VERSION 5.7 ;
  NOWIREEXTENSIONATPIN ON ;
  DIVIDERCHAR "/" ;
  BUSBITCHARS "[]" ;
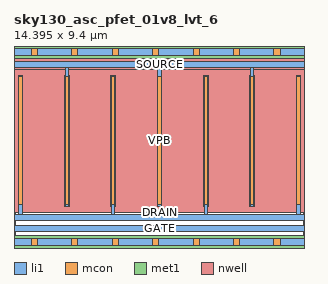
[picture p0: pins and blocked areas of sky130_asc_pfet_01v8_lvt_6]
MACRO sky130_asc_pfet_01v8_lvt_6
  CLASS CORE ;
  FOREIGN sky130_asc_pfet_01v8_lvt_6 ;
  ORIGIN 0.000 0.000 ;
  SIZE 14.395 BY 9.400 ;
  SITE unitasc ;
  PIN GATE
    DIRECTION INOUT ;
    USE SIGNAL ;
    ANTENNAGATEAREA 77.400002 ;
    PORT
      LAYER li1 ;
        RECT 0.010 0.520 14.390 0.820 ;
    END
  END GATE
  PIN SOURCE
    DIRECTION INOUT ;
    USE SIGNAL ;
    ANTENNADIFFAREA 5.611500 ;
    PORT
      LAYER li1 ;
        RECT 0.010 8.650 14.390 8.950 ;
        RECT 2.535 1.755 2.705 8.650 ;
        RECT 7.115 1.755 7.285 8.650 ;
        RECT 11.695 1.755 11.865 8.650 ;
      LAYER mcon ;
        RECT 2.535 1.835 2.705 8.165 ;
        RECT 7.115 1.835 7.285 8.165 ;
        RECT 11.695 1.835 11.865 8.165 ;
      LAYER met1 ;
        RECT 2.505 1.775 2.735 8.225 ;
        RECT 7.085 1.775 7.315 8.225 ;
        RECT 11.665 1.775 11.895 8.225 ;
    END
  END SOURCE
  PIN DRAIN
    DIRECTION INOUT ;
    USE SIGNAL ;
    ANTENNADIFFAREA 7.482000 ;
    PORT
      LAYER li1 ;
        RECT 0.245 1.350 0.415 8.245 ;
        RECT 4.825 1.350 4.995 8.245 ;
        RECT 9.405 1.350 9.575 8.245 ;
        RECT 13.985 1.350 14.155 8.245 ;
        RECT 0.010 1.050 14.390 1.350 ;
      LAYER mcon ;
        RECT 0.245 1.835 0.415 8.165 ;
        RECT 4.825 1.835 4.995 8.165 ;
        RECT 9.405 1.835 9.575 8.165 ;
        RECT 13.985 1.835 14.155 8.165 ;
      LAYER met1 ;
        RECT 0.215 1.775 0.445 8.225 ;
        RECT 4.795 1.775 5.025 8.225 ;
        RECT 9.375 1.775 9.605 8.225 ;
        RECT 13.955 1.775 14.185 8.225 ;
    END
  END DRAIN
  PIN VPB
    DIRECTION INOUT ;
    USE POWER ;
    PORT
      LAYER nwell ;
        RECT 0.010 8.535 14.390 9.700 ;
        RECT 0.005 1.465 14.395 8.535 ;
    END
  END VPB
  PIN VPWR
    DIRECTION INOUT ;
    USE POWER ;
    PORT
      LAYER li1 ;
        RECT 0.010 9.250 14.390 9.550 ;
      LAYER mcon ;
        RECT 0.860 9.250 1.160 9.550 ;
        RECT 2.860 9.250 3.160 9.550 ;
        RECT 4.860 9.250 5.160 9.550 ;
        RECT 6.860 9.250 7.160 9.550 ;
        RECT 8.860 9.250 9.160 9.550 ;
        RECT 10.860 9.250 11.160 9.550 ;
        RECT 12.860 9.250 13.160 9.550 ;
      LAYER met1 ;
        RECT 0.010 9.100 14.390 9.700 ;
    END
  END VPWR
  PIN VGND
    DIRECTION INOUT ;
    USE GROUND ;
    PORT
      LAYER li1 ;
        RECT 0.010 -0.150 14.390 0.150 ;
      LAYER mcon ;
        RECT 0.860 -0.150 1.160 0.150 ;
        RECT 2.860 -0.150 3.160 0.150 ;
        RECT 4.860 -0.150 5.160 0.150 ;
        RECT 6.860 -0.150 7.160 0.150 ;
        RECT 8.860 -0.150 9.160 0.150 ;
        RECT 10.860 -0.150 11.160 0.150 ;
        RECT 12.860 -0.150 13.160 0.150 ;
      LAYER met1 ;
        RECT 0.010 -0.300 14.390 0.300 ;
    END
  END VGND
END sky130_asc_pfet_01v8_lvt_6
END LIBRARY

